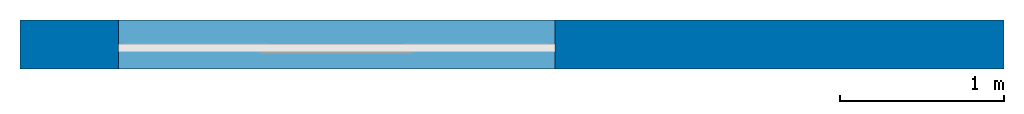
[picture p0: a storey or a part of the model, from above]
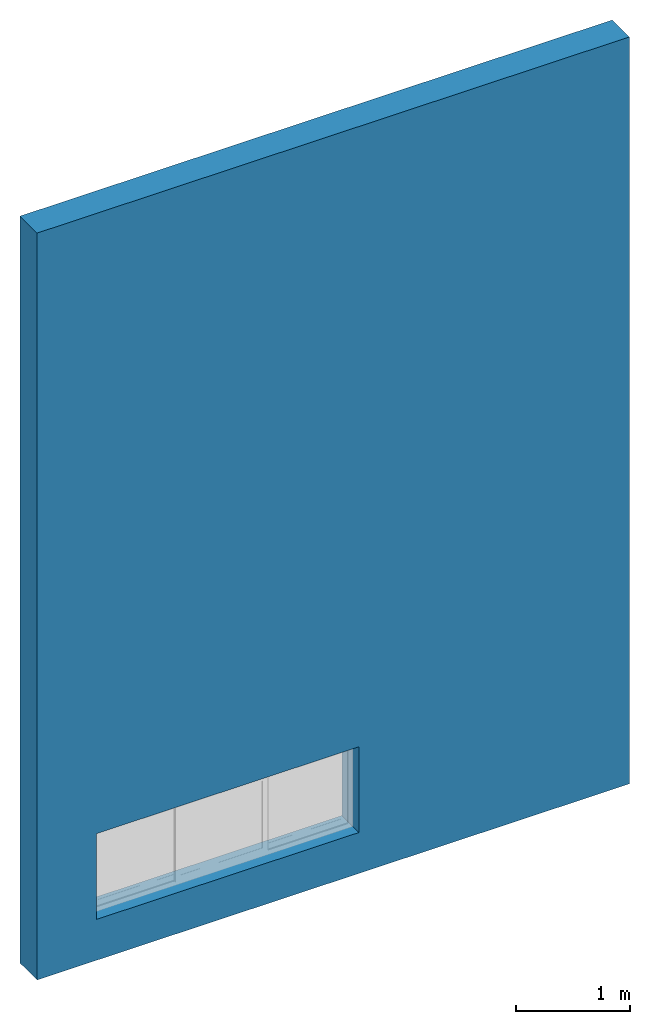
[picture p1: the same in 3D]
Properties of the parts of a building model (IFC2X3)

# File
Description: ViewDefinition [CoordinationView_V2.0]
File name: 0001
Time: 2021-01-26T08:14:04
Written by: The EXPRESS Data Manager Version 5.02.0100.07 : 28 Aug 2013
Made in: 20180328_1600(x64) - Exporter 19.0.1.1 - IU alternativa 19.0.1.1
Comment: STEP Physical File produced by: The EXPRESS Data Manager Version 5.02.0100.07 : 28 Aug 2013 * Module: EDMstepFileFactory/EDMstandAlone * Creation date: Tue Jan 26 08:14:04 2021 * Host: DESKTOP-H3U9LF2 * Database: C:\Users\BIMTOOL3\AppData\Local\Temp\{F2099087-418B-426B-A9DE-5AE202E7E695}\ifc * Database version: 5507 * Database creation date: Tue Jan 26 08:14:02 2021 * Schema: IFC2X3 * Model: DataRepository.ifc * Model creation date: Tue Jan 26 08:14:03 2021 * Header model: DataRepository.ifc_HeaderModel * Header model creation date: Tue Jan 26 08:14:03 2021 * EDMuser: sdai-user * EDMgroup: sdai-group * License ID and type: 5605 : Permanent license. Expiry date: * EDMstepFileFactory options: 020000

# IfcProject, 0001
LongName: Nombre de proyecto; Phase: Estado de proyecto

# IfcSite, Default
RefLatitude: 42, 12, 46, 804504; RefLongitude: -71, -2, 0, -602416; RefElevation: 0 mm

# IfcBuilding
Pset_BuildingCommon - NumberOfStoreys: 1

# IfcBuildingStorey, Nivel 1
LongName: Nivel 1; Elevation: 0 mm

# IfcBuildingElementProxy: 47.1 REH_EX-SLIDE_M2-EX_H1-EX_3 HOJAS, 47.1 REH_EX-SLIDE_M2-EX_H1-EX_3 HOJAS:47.1 REH_EX-SLIDE_M2-EX_H1-EX_3 HOJAS:371175
In: Nivel 1
Type - Material: Cristal, RAU-PVC
Pset_BuildingElementProxyCommon - Reference: 47.1 REH_EX-SLIDE_M2-EX_H1-EX_3 HOJAS
Pset_ManufacturerTypeInformation - Manufacturer: REHAU

# IfcWallStandardCase: Muro básico:Genérico - 300 mm, Muro básico:Genérico - 300 mm:344435
In: Nivel 1
Type - PredefinedType: STANDARD; Material: Muro por defecto 300 mm
Pset_WallCommon - Reference: Genérico - 300 mm; LoadBearing: no; ExtendToStructure: no; IsExternal: yes
